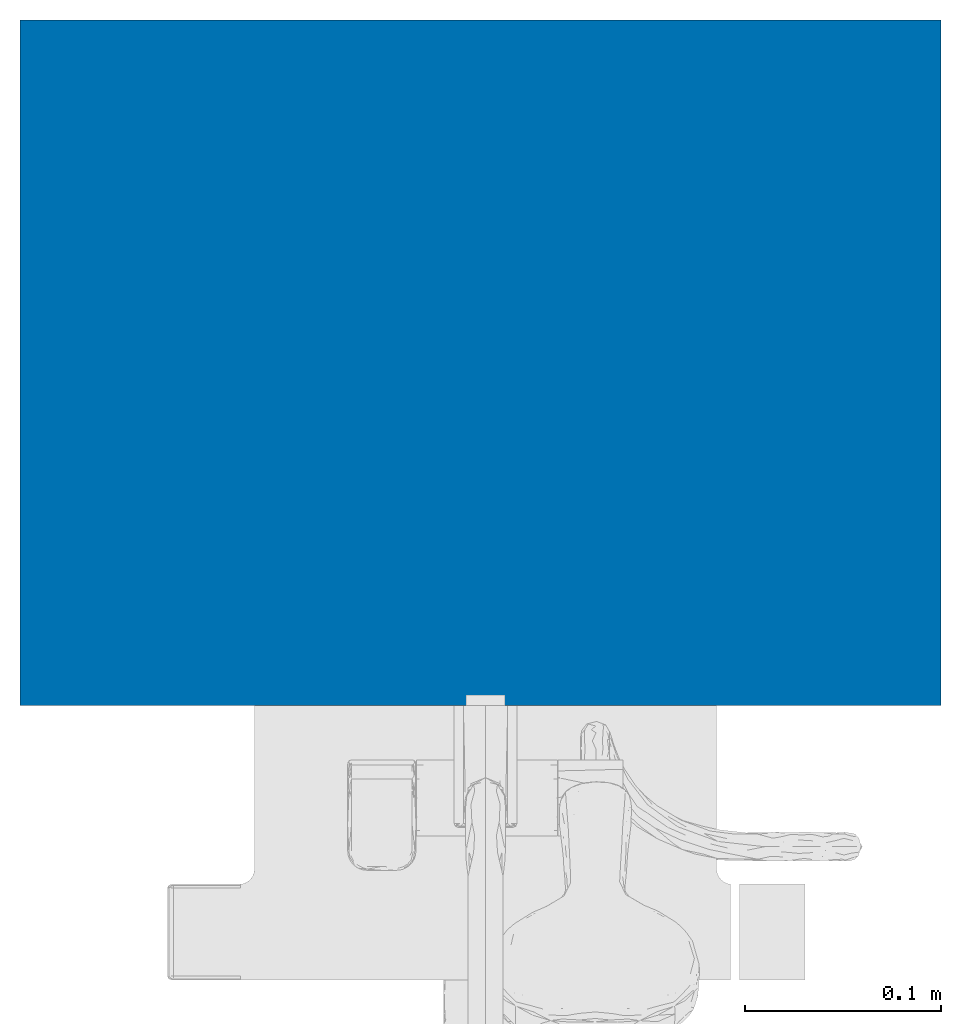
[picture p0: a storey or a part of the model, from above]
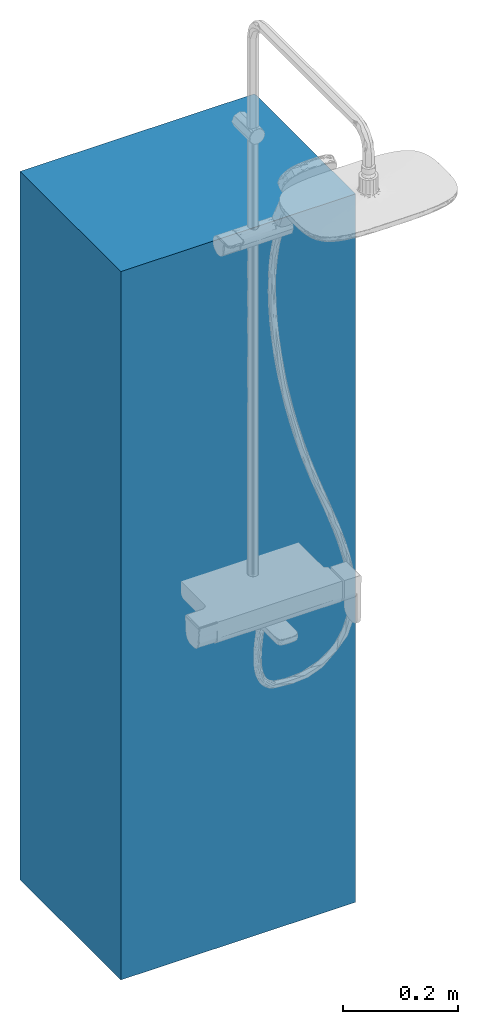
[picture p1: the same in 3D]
Properties of the parts of a building model (IFC2X3)

# File
Description: ViewDefinition [CoordinationView_V2.0]
File name: 0001
Time: 2022-11-07T14:14:54
Written by: The EXPRESS Data Manager Version 5.02.0100.07 : 28 Aug 2013
Made in: 20190808_0900(x64) - Exporter 19.2.20.24 - Alternate UI 19.2.20.24
Comment: STEP Physical File produced by: The EXPRESS Data Manager Version 5.02.0100.07 : 28 Aug 2013 * Module: EDMstepFileFactory/EDMstandAlone * Creation date: Mon Nov 07 14:14:54 2022 * Host: CHATPONG-DEE * Database: C:\Users\CHATPONG\AppData\Local\Temp\{57000D21-3467-4FCF-9280-DC75D8153810}\ifc * Database version: 5507 * Database creation date: Mon Nov 07 14:14:52 2022 * Schema: IFC2X3 * Model: DataRepository.ifc * Model creation date: Mon Nov 07 14:14:52 2022 * Header model: DataRepository.ifc_HeaderModel * Header model creation date: Mon Nov 07 14:14:52 2022 * EDMuser: sdai-user * EDMgroup: sdai-group * License ID and type: 5605 : Permanent license. Expiry date: * EDMstepFileFactory options: 020000

# IfcProject, 0001
LongName: Project Name; Phase: Project Status

# IfcSite, Default
RefLatitude: 42, 21, 31, 181945; RefLongitude: -71, -3, -24, -263305; RefElevation: 0 mm

# IfcBuilding
Pset_BuildingCommon - NumberOfStoreys: 1

# IfcBuildingStorey, Level 1
LongName: Level 1; Elevation: 0 mm

# IfcFlowTerminal: Type 1, FB0635S1-F_REVIT:Type 1:357745
In: Level 1
Material: Steel, Chrome Plated
Pset_DistributionFlowElementCommon - Reference: Type 1

# IfcWallStandardCase: Basic Wall:Exterior - Brick on Mtl. Stud, Basic Wall:Exterior - Brick on Mtl. Stud:357719
In: Level 1
Type - PredefinedType: STANDARD; Material: Brick, Common 90 mm, Air 76 mm, Plywood, Sheathing 19 mm, Metal Stud Layer 152 mm, Gypsum Wall Board 13 mm
Pset_WallCommon - Reference: Exterior - Brick on Mtl. Stud; LoadBearing: no; ExtendToStructure: no; IsExternal: yes; ThermalTransmittance: 0.105419 kg/K/s3
